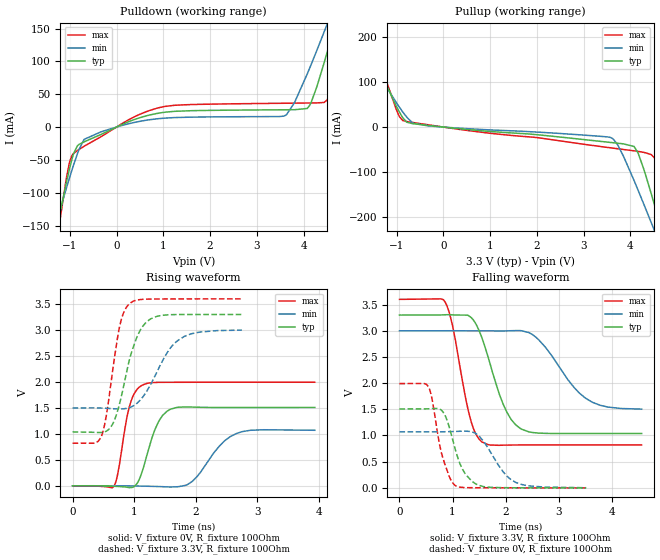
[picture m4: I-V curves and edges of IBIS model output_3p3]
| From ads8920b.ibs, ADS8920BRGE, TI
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|   output_3p3 Model
[Model]   output_3p3
Model_type   Output
Polarity   Non-Inverting
Vmeas = 1.65
Vref = 0
Cref = 20pF
Rref = 250
|   typ   min   max
|   (nom PVT)   (fast PVT)   (slow PVT)
C_comp   1.340e-12   1.328e-12   1.340e-12
| Where nom  PVT is Nominal Process, 3.3V, 27C
|   Fast PVT is Strong Process,  3.6V, -40C
|   Slow PVT is Weak Process,   3V, 125C
[Voltage Range]   3.3   3   3.6
|Junction Temperature
[Temperature Range]   27   125   -40
[Pullup Reference]   3.3   3   3.6
[Pulldown Reference]   0   0   0
[Power Clamp Reference]   3.3   3   3.6
[GND Clamp Reference]   0   0   0
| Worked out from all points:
|   slope of the pulldown table from 0 to 0.495 V, typ, clamps not added: 35 ohm
|   slope of the pullup table from 0 to 0.495 V, typ, clamps not added: 95 ohm
|   falling waveform, V_fixture 3.3V, R_fixture 100Ohm: 20-80 % time 442ps typ, 660ps min, 311ps max; typ from 3.3 V to 1.04 V
|   rising waveform, V_fixture 0V, R_fixture 100Ohm: 20-80 % time 248ps typ, 412ps min, 182ps max; typ from 0 V to 1.51 V
|   rising waveform, V_fixture 3.3V, R_fixture 100Ohm: 20-80 % time 297ps typ, 426ps min, 208ps max; typ from 1.04 V to 3.3 V
|   falling waveform, V_fixture 0V, R_fixture 100Ohm: 20-80 % time 295ps typ, 425ps min, 242ps max; typ from 1.51 V to 0 V
[Pulldown]
|   Voltage   I(typ)   I(min)   I(max)
-3.3V     -914mA     -673.4mA   -1.237A
-1.28V    -155.7mA   -143.9mA   -174.9mA
-951mV    -48.14mA   -64.81mA   -42.93mA
-693mV    -22.47mA   -18.73mA   -29.18mA
-330mV    -11.15mA   -7.178mA   -14.61mA
1.024V    22.5mA     13.58mA    31.24mA
3.627V    26.36mA    18.28mA    36.33mA
4.131V    32.89mA    89.65mA    36.7mA
4.508V    114.6mA    157.2mA    41.49mA
4.678V    157.5mA    188.2mA    85.05mA
4.841V    199.5mA    218.1mA    140.2mA
6.6V      643.9mA    531.2mA    758.2mA
[Pullup]
|   Voltage   I(typ)   I(min)   I(max)
-3.3V     614.2mA    461.8mA    817mA
-2.436V   401.3mA    309.7mA    524.3mA
-1.41V    140.1mA    123.7mA    164.7mA
-1.018V   48.36mA    55.87mA    41.62mA
-870mV    20.66mA    33.53mA    14.6mA
-330mV    3.756mA    2.556mA    5.137mA
3.579V    -34.13mA   -23.31mA   -46.03mA
4.079V    -42.96mA   -118.4mA   -52.63mA
4.516V    -172.4mA   -229.7mA   -68.23mA
4.768V    -264.4mA   -295.5mA   -172.7mA
4.976V    -342mA     -350.4mA   -277.7mA
6.6V      -957.2mA   -782.7mA   -1.133A
[Ramp]
R_load = 100
|   typ   min   max
dV/dt_r   0.905351/2.46002e-10  0.642223/4.11211e-10   1.19723/1.80964e-10
dV/dt_f   1.35762/4.40825e-10   0.900232/6.60977e-10   1.66818/3.10202e-10
[Falling Waveform]
V_fixture = 3.3V
V_fixture_min = 3V
V_fixture_max = 3.6V
R_fixture = 100Ohm
|   Time   V(typ)   V(min)   V(max)
0s        3.3V       3V         3.6V
860ps     3.306V     3V         3.549V
1.002ns   3.304V     3V         3.084V
1.346ns   3.256V     2.998V     1.28V
1.554ns   2.862V     2.999V     875.9mV
1.95ns    1.604V     2.997V     815.5mV
2.276ns   1.133V     3.003V     819.2mV
2.626ns   1.045V     2.822V     820.1mV
3.502ns   1.038V     1.713V     819.8mV
4.558ns   1.038V     1.504V     819.7mV
[Rising Waveform]
V_fixture = 0V
V_fixture_min = 0V
V_fixture_max = 0V
R_fixture = 100Ohm
|   Time   V(typ)   V(min)   V(max)
0s        1.943nV    4.589nV    1.654nV
670ps     -9.487mV   349.5uV    -8.771mV
736ps     -13.11mV   128.2uV    245.5mV
922ps     -35.71mV   -1.888mV   1.523V
1.126ns   261.4mV    -6.585mV   1.935V
1.342ns   1.097V     -12.9mV    1.99V
1.592ns   1.477V     -23.59mV   1.993V
1.942ns   1.516V     84.36mV    1.994V
2.668ns   1.507V     1.011V     1.995V
3.93ns    1.509V     1.069V     1.995V
[Rising Waveform]
V_fixture = 3.3V
V_fixture_min = 3V
V_fixture_max = 3.6V
R_fixture = 100Ohm
|   Time   V(typ)   V(min)   V(max)
0s        1.037V     1.5V       819.7mV
466ps     1.027V     1.497V     947.5mV
548ps     1.052V     1.492V     1.354V
654ps     1.195V     1.484V     2.249V
758ps     1.558V     1.479V     3.037V
916ps     2.397V     1.502V     3.5V
1.058ns   2.903V     1.602V     3.58V
1.202ns   3.157V     1.818V     3.595V
1.72ns    3.298V     2.807V     3.599V
2.748ns   3.299V     2.998V     3.6V
[Falling Waveform]
V_fixture = 0V
V_fixture_min = 0V
V_fixture_max = 0V
R_fixture = 100Ohm
|   Time   V(typ)   V(min)   V(max)
0s        1.507V     1.07V      1.991V
554ps     1.51V      1.07V      1.918V
792ps     1.481V     1.071V     662.5mV
898ps     1.285V     1.072V     330.2mV
1.056ns   715.8mV    1.077V     41.36mV
1.23ns    281.2mV    1.083V     5.376mV
1.508ns   44.48mV    978.7mV    1.44mV
1.948ns   3.845mV    311.7mV    338.1uV
2.194ns   1.367mV    101.2mV    239uV
3.514ns   173uV      2.36mV     21.17uV
